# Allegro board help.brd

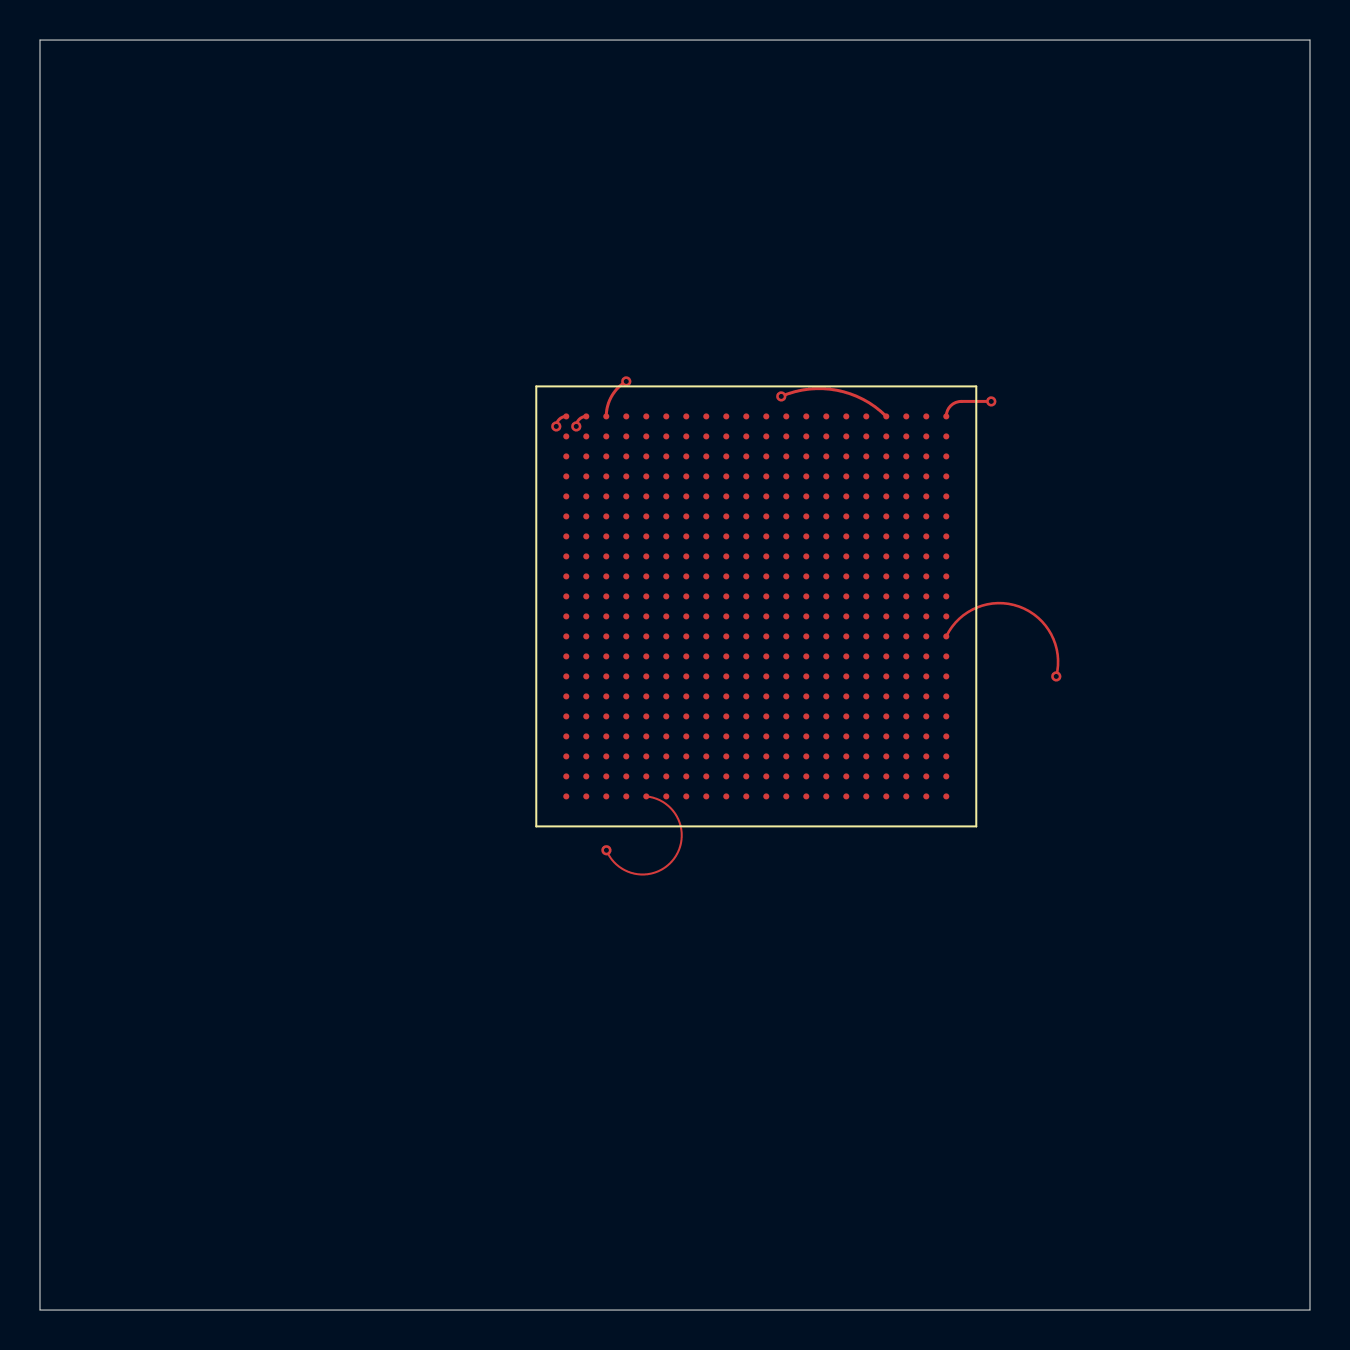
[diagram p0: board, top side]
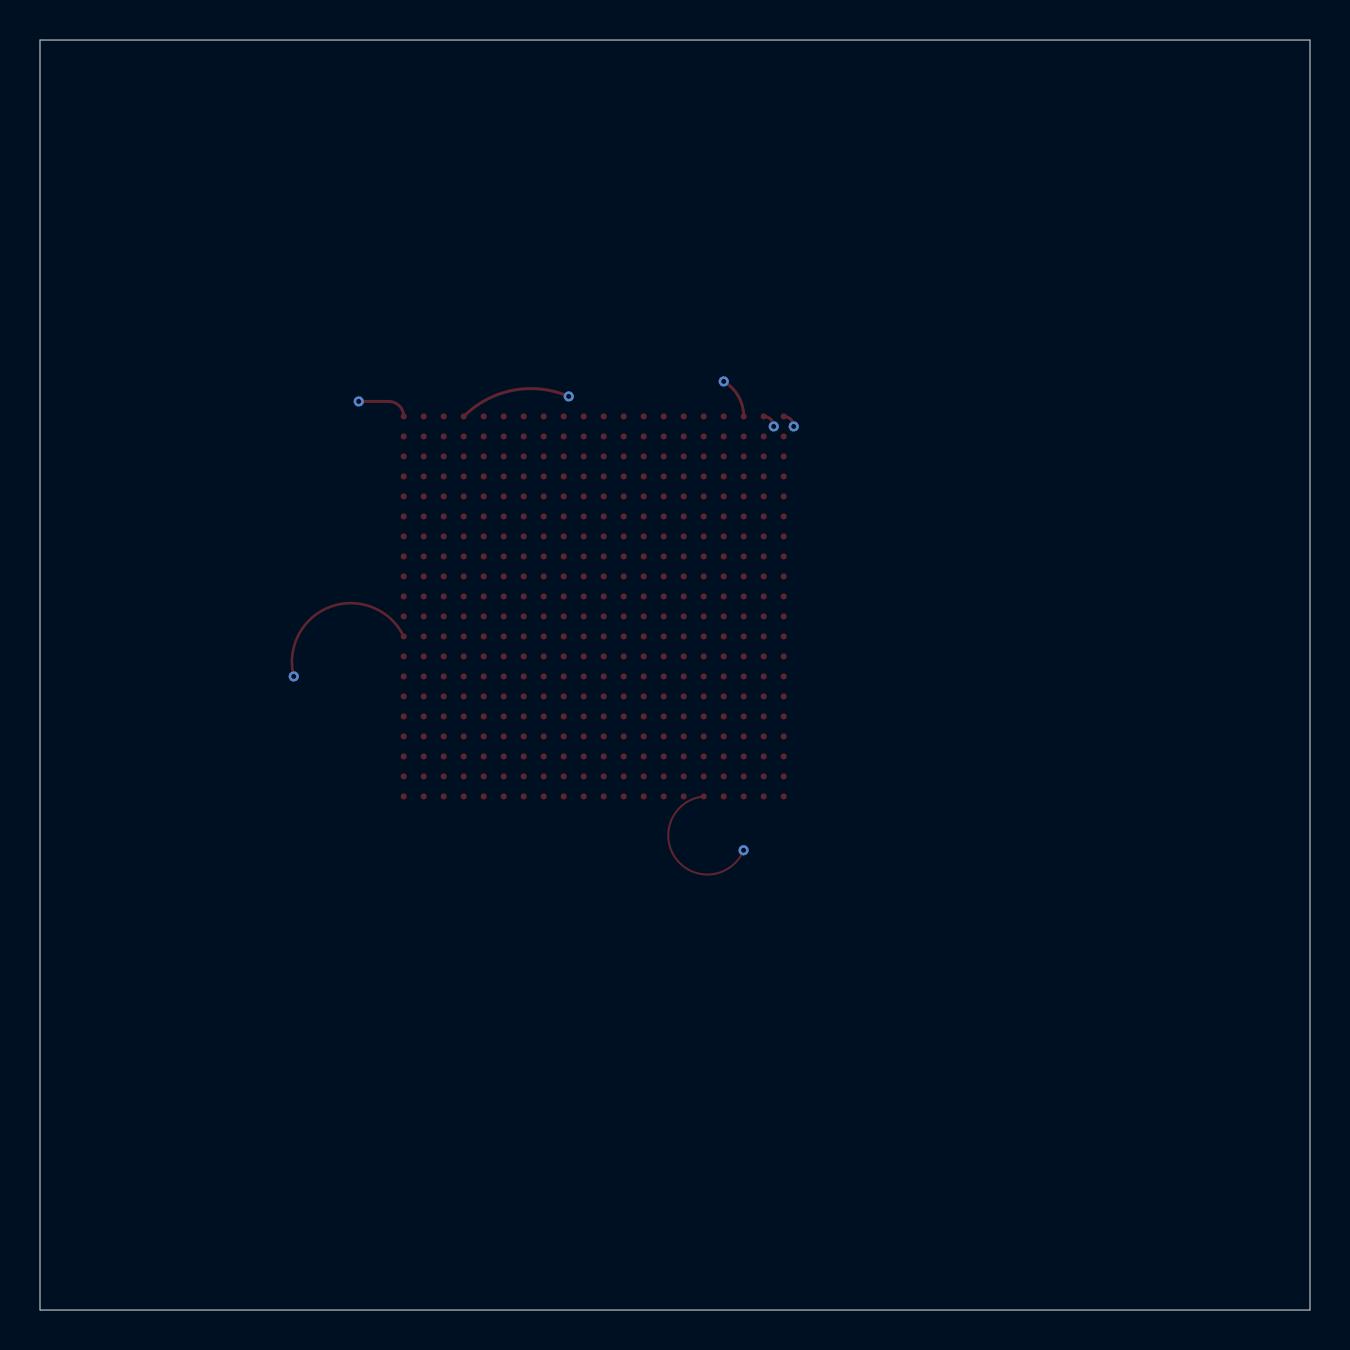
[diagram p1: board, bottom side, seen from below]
Outline 63.5 x 63.5 mm; copper layers: TOP, GND, VCC, BOTTOM. Coordinates in mm from the lower left corner of the outline.
Outline path: 0,63.5 63.5,63.5 63.5,0 0,0 0,63.5

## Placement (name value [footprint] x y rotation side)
U*  -  [unnamed]  35.81 35.18 0 top

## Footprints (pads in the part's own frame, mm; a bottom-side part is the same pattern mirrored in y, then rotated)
unnamed
  round 0.305 smd: A1(-9.5,9.5) A2(-8.5,9.5) A3(-7.5,9.5) A4(-6.5,9.5) A5(-5.5,9.5) A6(-4.5,9.5) A7(-3.5,9.5) A8(-2.5,9.5) A9(-1.5,9.5) A10(-0.5,9.5) A11(0.5,9.5) A12(1.5,9.5) A13(2.5,9.5) A14(3.5,9.5) A15(4.5,9.5) A16(5.5,9.5) A17(6.5,9.5) A18(7.5,9.5) A19(8.5,9.5) A20(9.5,9.5) B1(-9.5,8.5) B2(-8.5,8.5) B3(-7.5,8.5) B4(-6.5,8.5) B5(-5.5,8.5) B6(-4.5,8.5) B7(-3.5,8.5) B8(-2.5,8.5) B9(-1.5,8.5) B10(-0.5,8.5) B11(0.5,8.5) B12(1.5,8.5) B13(2.5,8.5) B14(3.5,8.5) B15(4.5,8.5) B16(5.5,8.5) B17(6.5,8.5) B18(7.5,8.5) B19(8.5,8.5) B20(9.5,8.5) C1(-9.5,7.5) C2(-8.5,7.5) C3(-7.5,7.5) C4(-6.5,7.5) C5(-5.5,7.5) C6(-4.5,7.5) C7(-3.5,7.5) C8(-2.5,7.5) C9(-1.5,7.5) C10(-0.5,7.5) C11(0.5,7.5) C12(1.5,7.5) C13(2.5,7.5) C14(3.5,7.5) C15(4.5,7.5) C16(5.5,7.5) C17(6.5,7.5) C18(7.5,7.5) C19(8.5,7.5) C20(9.5,7.5) D1(-9.5,6.5) D2(-8.5,6.5) D3(-7.5,6.5) D4(-6.5,6.5) D5(-5.5,6.5) D6(-4.5,6.5) D7(-3.5,6.5) D8(-2.5,6.5) D9(-1.5,6.5) D10(-0.5,6.5) D11(0.5,6.5) D12(1.5,6.5) D13(2.5,6.5) D14(3.5,6.5) D15(4.5,6.5) D16(5.5,6.5) D17(6.5,6.5) D18(7.5,6.5) D19(8.5,6.5) D20(9.5,6.5) E1(-9.5,5.5) E2(-8.5,5.5) E3(-7.5,5.5) E4(-6.5,5.5) E5(-5.5,5.5) E6(-4.5,5.5) E7(-3.5,5.5) E8(-2.5,5.5) E9(-1.5,5.5) E10(-0.5,5.5) E11(0.5,5.5) E12(1.5,5.5) E13(2.5,5.5) E14(3.5,5.5) E15(4.5,5.5) E16(5.5,5.5) E17(6.5,5.5) E18(7.5,5.5) E19(8.5,5.5) E20(9.5,5.5) F1(-9.5,4.5) F2(-8.5,4.5) F3(-7.5,4.5) F4(-6.5,4.5) F5(-5.5,4.5) F6(-4.5,4.5) F7(-3.5,4.5) F8(-2.5,4.5) F9(-1.5,4.5) F10(-0.5,4.5) F11(0.5,4.5) F12(1.5,4.5) F13(2.5,4.5) F14(3.5,4.5) F15(4.5,4.5) F16(5.5,4.5) F17(6.5,4.5) F18(7.5,4.5) F19(8.5,4.5) F20(9.5,4.5) G1(-9.5,3.5) G2(-8.5,3.5) G3(-7.5,3.5) G4(-6.5,3.5) G5(-5.5,3.5) G6(-4.5,3.5) G7(-3.5,3.5) G8(-2.5,3.5) G9(-1.5,3.5) G10(-0.5,3.5) G11(0.5,3.5) G12(1.5,3.5) G13(2.5,3.5) G14(3.5,3.5) G15(4.5,3.5) G16(5.5,3.5) G17(6.5,3.5) G18(7.5,3.5) G19(8.5,3.5) G20(9.5,3.5) H1(-9.5,2.5) H2(-8.5,2.5) H3(-7.5,2.5) H4(-6.5,2.5) H5(-5.5,2.5) H6(-4.5,2.5) H7(-3.5,2.5) H8(-2.5,2.5) H9(-1.5,2.5) H10(-0.5,2.5) H11(0.5,2.5) H12(1.5,2.5) H13(2.5,2.5) H14(3.5,2.5) H15(4.5,2.5) H16(5.5,2.5) H17(6.5,2.5) H18(7.5,2.5) H19(8.5,2.5) H20(9.5,2.5) J1(-9.5,1.5) J2(-8.5,1.5) J3(-7.5,1.5) J4(-6.5,1.5) J5(-5.5,1.5) J6(-4.5,1.5) J7(-3.5,1.5) J8(-2.5,1.5) J9(-1.5,1.5) J10(-0.5,1.5) J11(0.5,1.5) J12(1.5,1.5) J13(2.5,1.5) J14(3.5,1.5) J15(4.5,1.5) J16(5.5,1.5) J17(6.5,1.5) J18(7.5,1.5) J19(8.5,1.5) J20(9.5,1.5) K1(-9.5,0.5) K2(-8.5,0.5) K3(-7.5,0.5) K4(-6.5,0.5) K5(-5.5,0.5) K6(-4.5,0.5) K7(-3.5,0.5) K8(-2.5,0.5) K9(-1.5,0.5) K10(-0.5,0.5) K11(0.5,0.5) K12(1.5,0.5) K13(2.5,0.5) K14(3.5,0.5) K15(4.5,0.5) K16(5.5,0.5) K17(6.5,0.5) K18(7.5,0.5) K19(8.5,0.5) K20(9.5,0.5) L1(-9.5,-0.5) L2(-8.5,-0.5) L3(-7.5,-0.5) L4(-6.5,-0.5) L5(-5.5,-0.5) L6(-4.5,-0.5) L7(-3.5,-0.5) L8(-2.5,-0.5) L9(-1.5,-0.5) L10(-0.5,-0.5) L11(0.5,-0.5) L12(1.5,-0.5) L13(2.5,-0.5) L14(3.5,-0.5) L15(4.5,-0.5) L16(5.5,-0.5) L17(6.5,-0.5) L18(7.5,-0.5) L19(8.5,-0.5) L20(9.5,-0.5) M1(-9.5,-1.5) M2(-8.5,-1.5) M3(-7.5,-1.5) M4(-6.5,-1.5) M5(-5.5,-1.5) M6(-4.5,-1.5) M7(-3.5,-1.5) M8(-2.5,-1.5) M9(-1.5,-1.5) M10(-0.5,-1.5) M11(0.5,-1.5) M12(1.5,-1.5) M13(2.5,-1.5) M14(3.5,-1.5) M15(4.5,-1.5) M16(5.5,-1.5) M17(6.5,-1.5) M18(7.5,-1.5) M19(8.5,-1.5) M20(9.5,-1.5) N1(-9.5,-2.5) N2(-8.5,-2.5) N3(-7.5,-2.5) N4(-6.5,-2.5) N5(-5.5,-2.5) N6(-4.5,-2.5) N7(-3.5,-2.5) N8(-2.5,-2.5) N9(-1.5,-2.5) N10(-0.5,-2.5) N11(0.5,-2.5) N12(1.5,-2.5) N13(2.5,-2.5) N14(3.5,-2.5) N15(4.5,-2.5) N16(5.5,-2.5) N17(6.5,-2.5) N18(7.5,-2.5) N19(8.5,-2.5) N20(9.5,-2.5) P1(-9.5,-3.5) P2(-8.5,-3.5) P3(-7.5,-3.5) P4(-6.5,-3.5) P5(-5.5,-3.5) P6(-4.5,-3.5) P7(-3.5,-3.5) P8(-2.5,-3.5) P9(-1.5,-3.5) P10(-0.5,-3.5) P11(0.5,-3.5) P12(1.5,-3.5) P13(2.5,-3.5) P14(3.5,-3.5) P15(4.5,-3.5) P16(5.5,-3.5) P17(6.5,-3.5) P18(7.5,-3.5) P19(8.5,-3.5) P20(9.5,-3.5) R1(-9.5,-4.5) R2(-8.5,-4.5) R3(-7.5,-4.5) R4(-6.5,-4.5) R5(-5.5,-4.5) R6(-4.5,-4.5) R7(-3.5,-4.5) R8(-2.5,-4.5) R9(-1.5,-4.5) R10(-0.5,-4.5) R11(0.5,-4.5) R12(1.5,-4.5) R13(2.5,-4.5) R14(3.5,-4.5) R15(4.5,-4.5) R16(5.5,-4.5) R17(6.5,-4.5) R18(7.5,-4.5) R19(8.5,-4.5) R20(9.5,-4.5) T1(-9.5,-5.5) T2(-8.5,-5.5) T3(-7.5,-5.5) T4(-6.5,-5.5) T5(-5.5,-5.5) T6(-4.5,-5.5) T7(-3.5,-5.5) T8(-2.5,-5.5) T9(-1.5,-5.5) T10(-0.5,-5.5) T11(0.5,-5.5) T12(1.5,-5.5) T13(2.5,-5.5) T14(3.5,-5.5) T15(4.5,-5.5) T16(5.5,-5.5) T17(6.5,-5.5) T18(7.5,-5.5) T19(8.5,-5.5) T20(9.5,-5.5) U1(-9.5,-6.5) U2(-8.5,-6.5) U3(-7.5,-6.5) U4(-6.5,-6.5) U5(-5.5,-6.5) U6(-4.5,-6.5) U7(-3.5,-6.5) U8(-2.5,-6.5) U9(-1.5,-6.5) U10(-0.5,-6.5) U11(0.5,-6.5) U12(1.5,-6.5) U13(2.5,-6.5) U14(3.5,-6.5) U15(4.5,-6.5) U16(5.5,-6.5) U17(6.5,-6.5) U18(7.5,-6.5) U19(8.5,-6.5) U20(9.5,-6.5) V1(-9.5,-7.5) V2(-8.5,-7.5) V3(-7.5,-7.5) V4(-6.5,-7.5) V5(-5.5,-7.5) V6(-4.5,-7.5) V7(-3.5,-7.5) V8(-2.5,-7.5) V9(-1.5,-7.5) V10(-0.5,-7.5) V11(0.5,-7.5) V12(1.5,-7.5) V13(2.5,-7.5) V14(3.5,-7.5) V15(4.5,-7.5) V16(5.5,-7.5) V17(6.5,-7.5) V18(7.5,-7.5) V19(8.5,-7.5) V20(9.5,-7.5) W1(-9.5,-8.5) W2(-8.5,-8.5) W3(-7.5,-8.5) W4(-6.5,-8.5) W5(-5.5,-8.5) W6(-4.5,-8.5) W7(-3.5,-8.5) W8(-2.5,-8.5) W9(-1.5,-8.5) W10(-0.5,-8.5) W11(0.5,-8.5) W12(1.5,-8.5) W13(2.5,-8.5) W14(3.5,-8.5) W15(4.5,-8.5) W16(5.5,-8.5) W17(6.5,-8.5) W18(7.5,-8.5) W19(8.5,-8.5) W20(9.5,-8.5) Y1(-9.5,-9.5) Y2(-8.5,-9.5) Y3(-7.5,-9.5) Y4(-6.5,-9.5) Y5(-5.5,-9.5) Y6(-4.5,-9.5) Y7(-3.5,-9.5) Y8(-2.5,-9.5) Y9(-1.5,-9.5) Y10(-0.5,-9.5) Y11(0.5,-9.5) Y12(1.5,-9.5) Y13(2.5,-9.5) Y14(3.5,-9.5) Y15(4.5,-9.5) Y16(5.5,-9.5) Y17(6.5,-9.5) Y18(7.5,-9.5) Y19(8.5,-9.5) Y20(9.5,-9.5)

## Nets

Pads without a net: U* A1 A2 A3 A4 A5 A6 A7 A8 A9 A10 A11 A12 A13 A14 A15 A16 A17 A18 A19 A20 B1 B2 B3 B4 B5 B6 B7 B8 B9 B10 B11 B12 B13 B14 B15 B16 B17 B18 B19 B20 C1 C2 C3 C4 C5 C6 C7 C8 C9 C10 C11 C12 C13 C14 C15 C16 C17 C18 C19 C20 D1 D2 D3 D4 D5 D6 D7 D8 D9 D10 D11 D12 D13 D14 D15 D16 D17 D18 D19 D20 E1 E2 E3 E4 E5 E6 E7 E8 E9 E10 E11 E12 E13 E14 E15 E16 E17 E18 E19 E20 F1 F2 F3 F4 F5 F6 F7 F8 F9 F10 F11 F12 F13 F14 F15 F16 F17 F18 F19 F20 G1 G2 G3 G4 G5 G6 G7 G8 G9 G10 G11 G12 G13 G14 G15 G16 G17 G18 G19 G20 H1 H2 H3 H4 H5 H6 H7 H8 H9 H10 H11 H12 H13 H14 H15 H16 H17 H18 H19 H20 J1 J2 J3 J4 J5 J6 J7 J8 J9 J10 J11 J12 J13 J14 J15 J16 J17 J18 J19 J20 K1 K2 K3 K4 K5 K6 K7 K8 K9 K10 K11 K12 K13 K14 K15 K16 K17 K18 K19 K20 L1 L2 L3 L4 L5 L6 L7 L8 L9 L10 L11 L12 L13 L14 L15 L16 L17 L18 L19 L20 M1 M2 M3 M4 M5 M6 M7 M8 M9 M10 M11 M12 M13 M14 M15 M16 M17 M18 M19 M20 N1 N2 N3 N4 N5 N6 N7 N8 N9 N10 N11 N12 N13 N14 N15 N16 N17 N18 N19 N20 P1 P2 P3 P4 P5 P6 P7 P8 P9 P10 P11 P12 P13 P14 P15 P16 P17 P18 P19 P20 R1 R2 R3 R4 R5 R6 R7 R8 R9 R10 R11 R12 R13 R14 R15 R16 R17 R18 R19 R20 T1 T2 T3 T4 T5 T6 T7 T8 T9 T10 T11 T12 T13 T14 T15 T16 T17 T18 T19 T20 U1 U2 U3 U4 U5 U6 U7 U8 U9 U10 U11 U12 U13 U14 U15 U16 U17 U18 U19 U20 V1 V2 V3 V4 V5 V6 V7 V8 V9 V10 V11 V12 V13 V14 V15 V16 V17 V18 V19 V20 W1 W2 W3 W4 W5 W6 W7 W8 W9 W10 W11 W12 W13 W14 W15 W16 W17 W18 W19 W20 Y1 Y2 Y3 Y4 Y5 Y6 Y7 Y8 Y9 Y10 Y11 Y12 Y13 Y14 Y15 Y16 Y17 Y18 Y19 Y20

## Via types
v1: diameter 0.508, hole 0.254, TOP to BOTTOM, 7 vias

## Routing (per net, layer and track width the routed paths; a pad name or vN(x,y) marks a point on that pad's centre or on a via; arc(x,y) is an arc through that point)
Net_1: length 0.8
  TOP w0.15: 26.31,44.68 arc(25.96,44.53) v1(25.81,44.18)
Net_2: length 0.8
  TOP w0.15: 27.31,44.68 arc(26.96,44.53) v1(26.81,44.18)
Net_3: length 2.1
  TOP w0.15: 28.31,44.68 arc(28.58,45.69) v1(29.31,46.43)
Net_17: length 5.7
  TOP w0.15: 42.31,44.68 arc(39.84,45.99) v1(37.06,45.68)
Net_20: length 2.7
  TOP w0.15: v1(47.56,45.43) 46.06,45.43 arc(45.53,45.21) 45.31,44.68
Net_240: length 8.7
  TOP w0.13: 45.31,33.68 arc(48.97,35.17) v1(50.81,31.68)
Net_385: length 8.3
  TOP w0.102: 30.31,25.68 arc(31.7,22.57) v1(28.32,22.99)
